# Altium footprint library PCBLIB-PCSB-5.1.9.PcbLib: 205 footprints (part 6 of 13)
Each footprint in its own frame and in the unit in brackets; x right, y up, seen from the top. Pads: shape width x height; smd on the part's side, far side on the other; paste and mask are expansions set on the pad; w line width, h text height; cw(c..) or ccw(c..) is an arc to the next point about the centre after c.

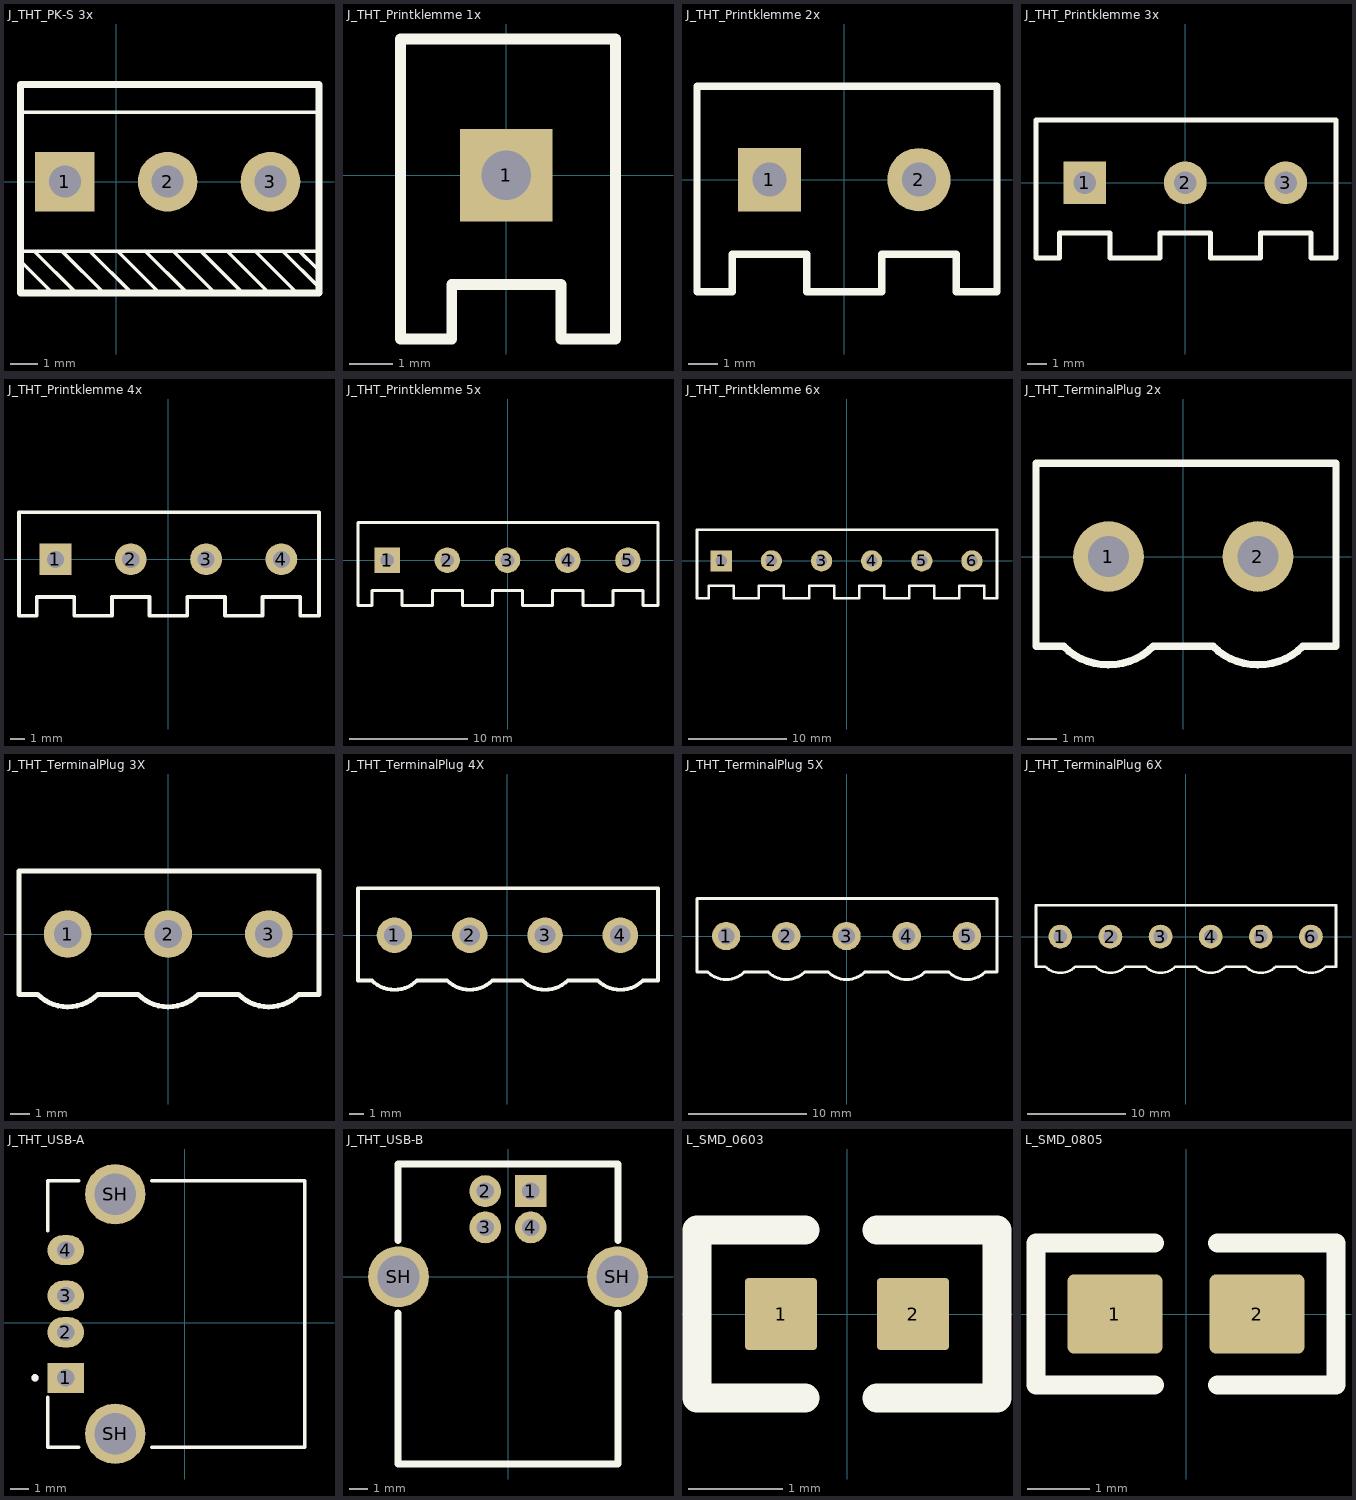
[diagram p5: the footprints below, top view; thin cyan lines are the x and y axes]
## J_THT_PK-S 3x [mm] "LB-2024-05-03g"
pads (3):
  rect 2.15x2.15 hole 1.15: 1(-1.85,0)
  round 2.15 hole 1.15: 2(1.85,0) 3(5.55,0)
Top Overlay:
  lines w0.127: -3.5,-2.5 6.5,-2.5 7.3,-2.5 ; -3.45,2.5 7.3,2.5 ; -3.4,-2.9 -2.3,-4 ; -1.95,-2.5 -0.45,-4 ; -1.45,-4 -2.95,-2.5 ; -0.95,-2.5 0.55,-4 ; 0.05,-2.5 1.55,-4 ; 1.05,-2.5 2.55,-4 ; 3.55,-4 2.05,-2.5 ; 4,-2.5 5.425,-3.925 ; 4.575,-4.025 3.05,-2.5 ; 5,-2.5 6.5,-4 ; 6,-2.5 7.3,-3.8 ; 7,-2.5 6.6,-2.5 7.25,-3.15 ; -2.95,-2.5 -2.95,-2.5 ; 2.05,-2.5 2.05,-2.5 ; 3.05,-2.5 3.05,-2.5 ; 3.05,-2.5 3.05,-2.5
  lines w0.254: -3.45,-4 -3.45,2.365 -3.45,3.5 7.3,3.5 7.3,-4 3.55,-4 -2.91,-4 -3.45,-4

## J_THT_Printklemme 1x [mm] "LB-2024-04-17"
pads (1):
  rect 2.15x2.15 hole 1.15: 1(0,0)
Top Overlay:
  lines w0.254: -2.46,-3.81 -2.46,2.365 -2.46,3.175 2.54,3.175 2.54,-3.81 1.27,-3.81 1.27,-2.54 -1.27,-2.54 -1.27,-3.81 -2.46,-3.81

## J_THT_Printklemme 2x [mm] "LB-2024-04-17"
pads (2):
  rect 2.15x2.15 hole 1.15: 1(-2.54,0)
  round 2.15 hole 1.15: 2(2.54,0)
Top Overlay:
  lines w0.254: 1.27,-3.81 1.27,-2.54 ; 1.27,-3.81 -1.27,-3.81 -1.27,-2.54 -3.81,-2.54 -3.81,-3.81 -5,-3.81 -5,2.365 -5,3.175 5.19,3.175 5.19,-3.81 3.81,-3.81 ; 1.27,-3.81 1.27,-2.54 ; 1.27,-2.54 3.81,-2.54 ; 3.81,-3.81 3.81,-2.54 ; 3.81,-3.81 3.81,-2.54

## J_THT_Printklemme 3x [mm] "LB-2024-04-17"
pads (3):
  rect 2.15x2.15 hole 1.15: 1(-5.08,0)
  round 2.15 hole 1.15: 2(0,0) 3(5.08,0)
Top Overlay:
  lines w0.254: -1.27,-3.81 -1.27,-2.54 ; -1.27,-3.81 -3.81,-3.81 -3.81,-2.54 -6.35,-2.54 -6.35,-3.81 -7.54,-3.81 -7.54,2.365 -7.54,3.175 2.65,3.175 7.62,3.175 7.62,-3.81 6.35,-3.81 6.35,-2.54 3.81,-2.54 3.81,-3.81 1.27,-3.81 ; -1.27,-3.81 -1.27,-2.54 ; -1.27,-2.54 1.27,-2.54 ; 1.27,-3.81 1.27,-2.54 ; 1.27,-3.81 1.27,-2.54

## J_THT_Printklemme 4x [mm] "LB-2024-04-17"
pads (4):
  rect 2.15x2.15 hole 1.15: 1(-7.62,0)
  round 2.15 hole 1.15: 2(-2.54,0) 3(2.54,0) 4(7.62,0)
Top Overlay:
  lines w0.254: -3.81,-3.81 -3.81,-2.54 ; -3.81,-3.81 -6.35,-3.81 -6.35,-2.54 -8.89,-2.54 -8.89,-3.81 -10.08,-3.81 -10.08,2.365 -10.08,3.175 0.11,3.175 10.16,3.175 10.16,-3.81 8.89,-3.81 8.89,-2.54 6.35,-2.54 6.35,-3.81 3.81,-3.81 3.81,-2.54 1.27,-2.54 1.27,-3.81 -1.27,-3.81 ; -3.81,-3.81 -3.81,-2.54 ; -3.81,-2.54 -1.27,-2.54 ; -1.27,-3.81 -1.27,-2.54 ; -1.27,-3.81 -1.27,-2.54

## J_THT_Printklemme 5x [mm] "LB-2024-04-17"
pads (5):
  rect 2.15x2.15 hole 1.15: 1(-10.16,0)
  round 2.15 hole 1.15: 2(-5.08,0) 3(0,0) 4(5.08,0) 5(10.16,0)
Top Overlay:
  lines w0.254: -6.35,-3.81 -6.35,-2.54 ; -6.35,-3.81 -8.89,-3.81 -8.89,-2.54 -11.43,-2.54 -11.43,-3.81 -12.62,-3.81 -12.62,2.365 -12.62,3.175 -2.43,3.175 12.7,3.175 12.7,-3.81 11.43,-3.81 11.43,-2.54 8.89,-2.54 8.89,-3.81 6.35,-3.81 6.35,-2.54 3.81,-2.54 3.81,-3.81 1.27,-3.81 1.27,-2.54 -1.27,-2.54 -1.27,-3.81 -3.81,-3.81 ; -6.35,-3.81 -6.35,-2.54 ; -6.35,-2.54 -3.81,-2.54 ; -3.81,-3.81 -3.81,-2.54 ; -3.81,-3.81 -3.81,-2.54

## J_THT_Printklemme 6x [mm] "LB-2024-04-17"
pads (6):
  rect 2.15x2.15 hole 1.15: 1(-12.7,0)
  round 2.15 hole 1.15: 2(-7.62,0) 3(-2.54,0) 4(2.54,0) 5(7.62,0) 6(12.7,0)
Top Overlay:
  lines w0.254: -8.89,-3.81 -8.89,-2.54 ; -8.89,-3.81 -11.43,-3.81 -11.43,-2.54 -13.97,-2.54 -13.97,-3.81 -15.16,-3.81 -15.16,2.365 -15.16,3.175 -4.97,3.175 15.24,3.175 15.24,-3.81 13.97,-3.81 13.97,-2.54 11.43,-2.54 11.43,-3.81 8.89,-3.81 8.89,-2.54 6.35,-2.54 6.35,-3.81 3.81,-3.81 3.81,-2.54 1.27,-2.54 1.27,-3.81 -1.27,-3.81 -1.27,-2.54 -3.81,-2.54 -3.81,-3.81 -6.35,-3.81 ; -8.89,-3.81 -8.89,-2.54 ; -8.89,-2.54 -6.35,-2.54 ; -6.35,-3.81 -6.35,-2.54 ; -6.35,-3.81 -6.35,-2.54

## J_THT_TerminalPlug 2x [mm] "LB-2024-04-17"
pads (2):
  round 2.4 hole 1.4: 1(-2.54,0) 2(2.54,0)
Top Overlay:
  lines w0.254: -5,-3.048 -4.064,-3.048 ccw(c-2.54,-1.524) -1.016,-3.048 1.016,-3.048 ccw(c2.54,-1.524) 4.064,-3.048 5.19,-3.048 5.19,3.175 -5,3.175 -5,2.365 -5,-3.048

## J_THT_TerminalPlug 3X [mm] "LB-2024-04-17"
pads (3):
  round 2.4 hole 1.4: 1(-5.08,0) 2(0,0) 3(5.08,0)
Top Overlay:
  lines w0.254: -7.54,-3.048 -7.54,2.365 -7.54,3.175 2.65,3.175 7.62,3.175 7.62,-3.048 6.604,-3.048 cw(c5.08,-1.524) 3.556,-3.048 1.524,-3.048 cw(c0,-1.524) -1.524,-3.048 -3.556,-3.048 cw(c-5.08,-1.524) -6.604,-3.048 -7.54,-3.048

## J_THT_TerminalPlug 4X [mm] "LB-2024-04-17"
pads (4):
  round 2.4 hole 1.4: 1(-7.62,0) 2(-2.54,0) 3(2.54,0) 4(7.62,0)
Top Overlay:
  lines w0.254: -10.08,-3.048 -10.08,2.365 -10.08,3.175 0.11,3.175 10.16,3.175 10.16,-3.048 9.144,-3.048 cw(c7.62,-1.524) 6.096,-3.048 4.064,-3.048 cw(c2.54,-1.524) 1.016,-3.048 -1.016,-3.048 cw(c-2.54,-1.524) -4.064,-3.048 -6.096,-3.048 cw(c-7.62,-1.524) -9.144,-3.048 -10.08,-3.048

## J_THT_TerminalPlug 5X [mm] "LB-2024-04-17"
pads (5):
  round 2.4 hole 1.4: 1(-10.16,0) 2(-5.08,0) 3(0,0) 4(5.08,0) 5(10.16,0)
Top Overlay:
  lines w0.254: -12.62,-3.048 -11.684,-3.048 ccw(c-10.16,-1.524) -8.636,-3.048 -6.604,-3.048 ccw(c-5.08,-1.524) -3.556,-3.048 -1.524,-3.048 ccw(c0,-1.524) 1.524,-3.048 3.556,-3.048 ccw(c5.08,-1.524) 6.604,-3.048 8.636,-3.048 ccw(c10.16,-1.524) 11.684,-3.048 12.7,-3.048 12.7,3.175 -2.43,3.175 -12.62,3.175 -12.62,2.365 -12.62,-3.048

## J_THT_TerminalPlug 6X [mm] "LB-2024-04-17"
pads (6):
  round 2.4 hole 1.4: 1(-12.7,0) 2(-7.62,0) 3(-2.54,0) 4(2.54,0) 5(7.62,0) 6(12.7,0)
Top Overlay:
  lines w0.254: -15.16,-3.048 -15.16,2.365 -15.16,3.175 -4.97,3.175 15.24,3.175 15.24,-3.048 14.224,-3.048 cw(c12.7,-1.524) 11.176,-3.048 9.144,-3.048 cw(c7.62,-1.524) 6.096,-3.048 4.064,-3.048 cw(c2.54,-1.524) 1.016,-3.048 -1.016,-3.048 cw(c-2.54,-1.524) -4.064,-3.048 -6.096,-3.048 cw(c-7.62,-1.524) -9.144,-3.048 -11.176,-3.048 cw(c-12.7,-1.524) -14.224,-3.048 -15.16,-3.048

## J_THT_USB-A [mm] "LB-2024-04-29"
pads (6):
  rect 2x1.65 hole 0.95: 1(-6.536,-3.032)
  oval 2x1.65 hole 0.95: 2(-6.536,-0.532) 3(-6.536,1.468) 4(-6.536,3.968)
  round 3.316 hole 2.3: SH(-3.826,-6.102) SH(-3.826,7.038)
Top Overlay:
  circle w0.2: c-8.226,-3.032 r0.1
  lines w0.2: -7.526,-4.097 -7.526,-6.832 -5.836,-6.832 ; -7.526,5.033 -7.526,7.768 -5.836,7.768 ; -1.816,-6.832 6.574,-6.832 6.574,7.768 -1.816,7.768
Mechanical 13:
  circle w0.2: c-8.226,-3.032 r0.1

## J_THT_USB-B [mm] "LB-2024-04-15"
pads (6):
  rect 1.75x1.75 hole 0.95: 1(1.25,4.71)
  round 1.75 hole 0.95: 2(-1.25,4.71) 3(-1.25,2.71) 4(1.25,2.71)
  round 3.346 hole 2.33: SH(-6.02,0) SH(6.02,0)
Top Overlay:
  lines w0.4: -6.05,-2 -6.05,-10.3 6.05,-10.3 6.05,-2 ; -6.05,2 -6.05,6.2 6.05,6.2 6.05,2

## L_SMD_0603 [mil] "LB-2024-04-17"
pads (2):
  rrect10% 30x30 smd paste-0.79 mask+1.97: 1(-27.5,0) 2(27.5,0)
Top Overlay:
  lines w12: -17.5,-35 -62.5,-35 -62.5,35 -17.5,35 ; 12.5,-35 62.5,-35 62.5,35 12.5,35

## L_SMD_0805 [mil] "LB-2024-04-17"
pads (2):
  rrect15% 60x50 smd paste-0.79 mask+1.97: 1(-45,0) 2(45,0)
Top Overlay:
  lines w12: -20,-45 -95,-45 -95,45 -20,45 ; 20,-45 95,-45 95,45 20,45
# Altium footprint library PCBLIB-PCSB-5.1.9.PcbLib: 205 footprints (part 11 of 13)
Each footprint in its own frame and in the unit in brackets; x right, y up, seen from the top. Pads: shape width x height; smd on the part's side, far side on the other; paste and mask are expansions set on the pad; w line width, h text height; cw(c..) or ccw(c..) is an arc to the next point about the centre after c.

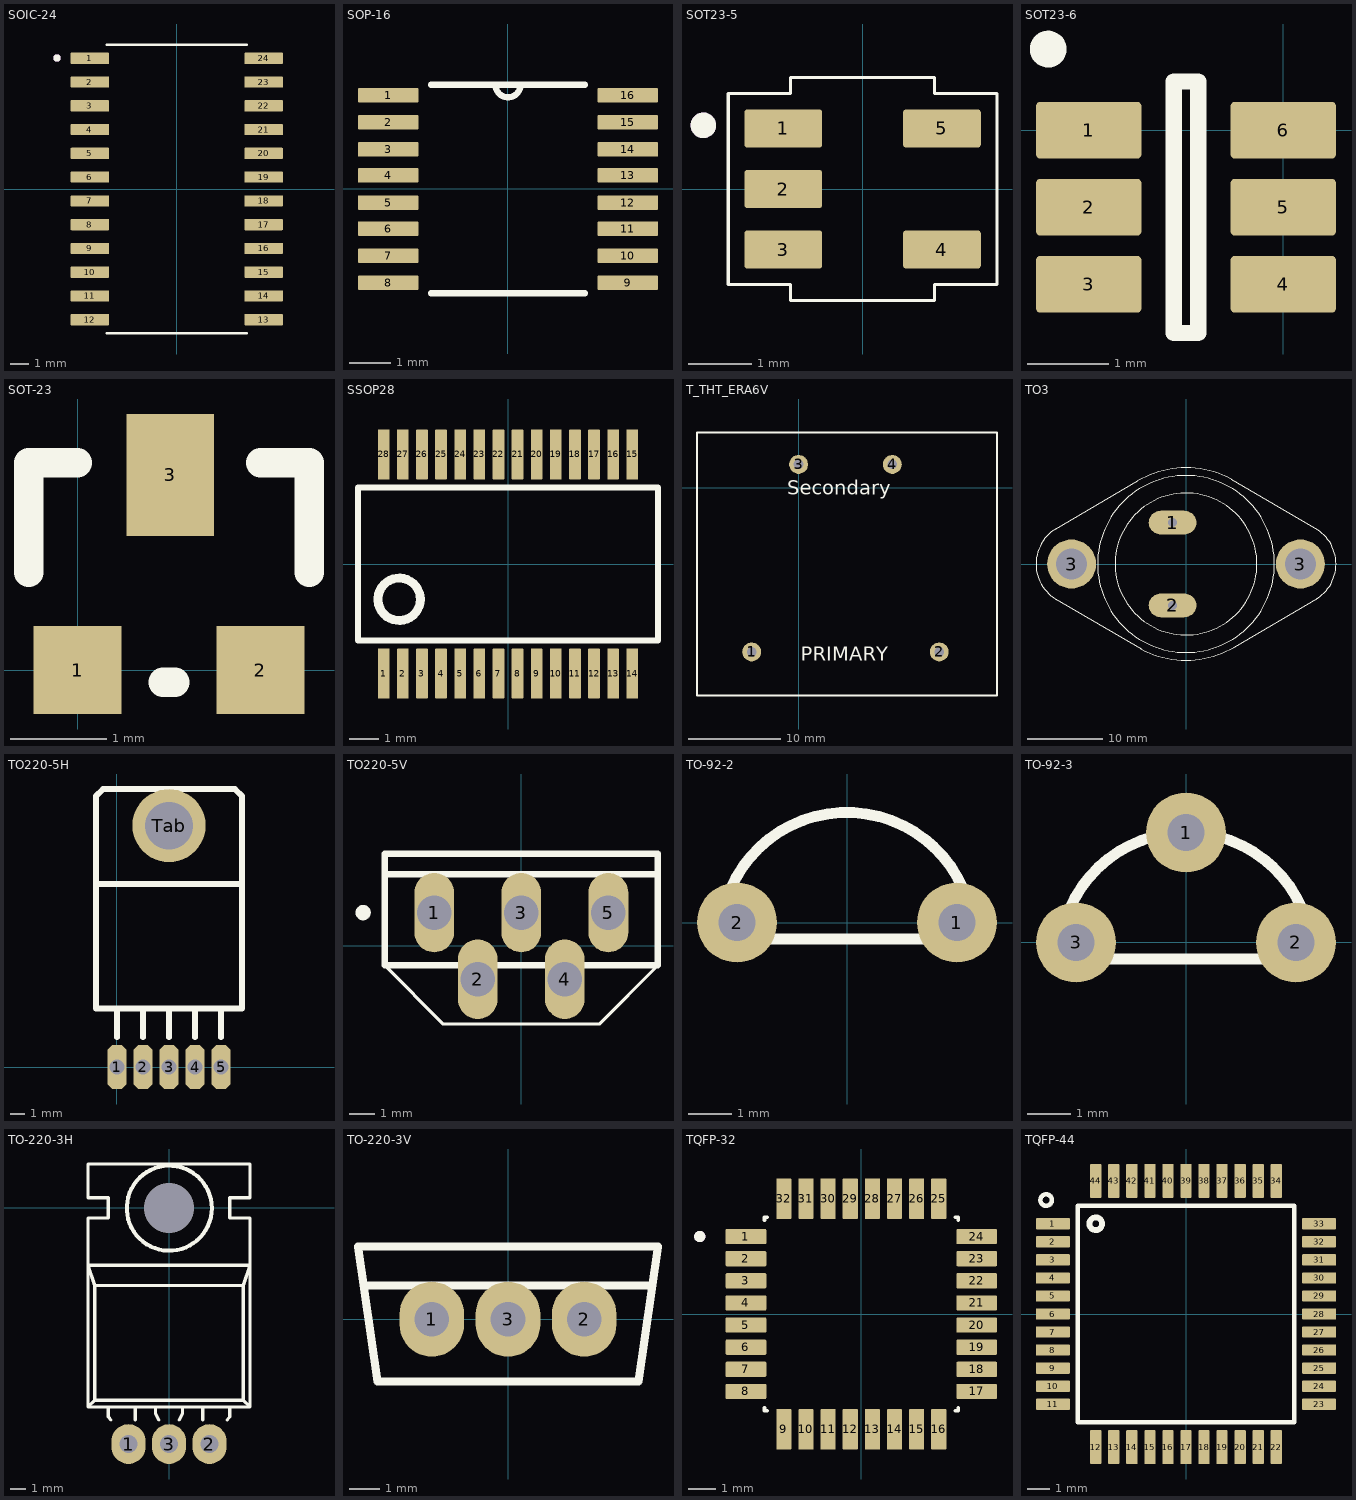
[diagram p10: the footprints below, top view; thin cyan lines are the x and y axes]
## SOIC-24 [mm]
height 2.65
pads (24):
  rrect15% 2.06x0.6 smd paste-0.02 mask+0.05: 1(-4.64,6.985) 2(-4.64,5.715) 3(-4.64,4.445) 4(-4.64,3.175) 5(-4.64,1.905) 6(-4.64,0.635) 7(-4.64,-0.635) 8(-4.64,-1.905) 9(-4.64,-3.175) 10(-4.64,-4.445) 11(-4.64,-5.715) 12(-4.64,-6.985) 13(4.64,-6.985) 14(4.64,-5.715) 15(4.64,-4.445) 16(4.64,-3.175) 17(4.64,-1.905) 18(4.64,-0.635) 19(4.64,0.635) 20(4.64,1.905) 21(4.64,3.175) 22(4.64,4.445) 23(4.64,5.715) 24(4.64,6.985)
Top Overlay:
  circle w0.2: c-6.4,7 r0.1
  lines w0.127: -3.75,-7.7 3.75,-7.7 ; -3.75,7.7 3.75,7.7
Mechanical 13:
  circle w0.2: c-6.4,7 r0.1

## SOP-16 [mil] "LB-2024-04-17"
pads (16):
  rrect15% 58x14 smd paste-0.79 mask+1.97: 1(-115,90) 2(-115,64) 3(-115,38) 4(-115,13) 5(-115,-13) 6(-115,-38) 7(-115,-64) 8(-115,-90) 9(115,-90) 10(115,-64) 11(115,-38) 12(115,-13) 13(115,13) 14(115,38) 15(115,64) 16(115,90)
Top Overlay:
  lines w6: -74,-100 74,-100 ; -74,100 -12,100 ; 74,100 12,100 ; -12,100 ccw(c0,100) 12,100 ; -12,100 12,100
Mechanical 13:
  lines w0: -12,100 ccw(c0,100) 12,100

## SOT23-5 [mm]
pads (5):
  rrect15% 1.22x0.6 smd paste-0.02 mask+0.05: 1(-1.245,0.95) 2(-1.245,0) 3(-1.245,-0.95) 4(1.245,-0.95) 5(1.245,0.95)
Top Overlay:
  circle w0.2: c-2.5,1 r0.1
  lines w0.05: -2.11,-1.5 -2.11,1.5 -1.13,1.5 -1.13,1.75 1.13,1.75 1.13,1.5 2.11,1.5 2.11,-1.5 1.13,-1.5 1.13,-1.75 -1.13,-1.75 -1.13,-1.5 -2.11,-1.5
Mechanical 13:
  circle w0.2: c-2.5,1 r0.1

## SOT23-6 [mm] "LB-2024-04-25"
height 1.45
pads (6):
  rrect15% 1.3x0.7 smd paste-0.02 mask+0.05: 1(-2.4,0) 2(-2.4,-0.95) 3(-2.4,-1.9) 4(0,-1.9) 5(0,-0.95) 6(0,0)
Top Overlay:
  circle w0.254: c-2.9,1 r0.1
  lines w0.2: -1.35,-2.5 -1.05,-2.5 -1.05,0.6 -1.35,0.6 -1.35,-2.5

## SOT-23 [mil]
pads (3):
  rect 36x36 smd: 1(0,0) 2(75,0)
  rect 36x50 smd: 3(38,80)
Top Overlay:
  lines w12: -20,40 -20,85 0,85 ; 35,-5 40,-5 ; 75,85 95,85 95,40

## SSOP28 [mm] "LB-2024-09-01"
pads (28):
  rrect15% 0.4x1.7 smd paste-0.02 mask+0.05: 1(-4.225,-3.725) 2(-3.575,-3.725) 3(-2.925,-3.725) 4(-2.275,-3.725) 5(-1.625,-3.725) 6(-0.975,-3.725) 7(-0.325,-3.725) 8(0.325,-3.725) 9(0.975,-3.725) 10(1.625,-3.725) 11(2.275,-3.725) 12(2.925,-3.725) 13(3.575,-3.725) 14(4.225,-3.725) 15(4.225,3.725) 16(3.575,3.725) 17(2.925,3.725) 18(2.275,3.725) 19(1.625,3.725) 20(0.975,3.725) 21(0.325,3.725) 22(-0.325,3.725) 23(-0.975,3.725) 24(-1.625,3.725) 25(-2.275,3.725) 26(-2.925,3.725) 27(-3.575,3.725) 28(-4.225,3.725)
Top Overlay:
  circle w0.3: c-3.7,-1.2 r0.721
  lines w0.203: -5.1,-2.6 -5.1,2.6 5.1,2.6 5.1,-2.6 -5.1,-2.6

## T_THT_ERA6V [mm] "LB-2024-04-17"
pads (4):
  round 2.05 hole 1.05: 1(-5.08,-17.78) 2(15.24,-17.78) 3(0,2.54) 4(10.16,2.54)
Top Overlay:
  lines w0.254: -11,-22.5 21.5,-22.5 21.5,6 -11,6 -11,-22.5
  text "PRIMARY" at 0.254,-18.746 h1.52
  text "Secondary" at -1.246,-0.738 h1.52

## TO3 [mil] "LB-2024-04-17"
pads (4):
  oval 248x124 hole 47.05: 1(-70,215) 2(-70,-215)
  round 255 hole 162: 3(-595,0) 3(595,0)
Top Overlay:
  circle w6: c0,0 r369
  circle w2: c0,0 r460
  lines w6: -680,180 -250,433 cw(c0,0) 0,500 cw(c0,0) 234.74,441.47 ; -679,-181 -234,-442 ; -676.7,-182.58 cw(c-567,0) -780,0 cw(c-567,0) -673.5,184.46 ; -234.74,-441.47 ccw(c0,0) 0,-500 ccw(c0,0) 250,-433.01 ; 235,441 684,178 ; 251,-433 684,-178 ; 683.01,-178.64 ccw(c567,0) 780,0 ccw(c567,0) 683.01,178.64
Mechanical 13:
  circle w6: c595,0 r85
  circle w6: c-595,0 r85

## TO220-5H [mm] "LB-2024-04-19"
height 5
pads (6):
  oct 1.3x3 hole 1.05: 1(0,0) 2(1.778,0) 3(3.556,0) 4(5.334,0) 5(7.112,0)
  round 5 hole 3.25: Tab(3.556,16.5)
Top Overlay:
  lines w0.4: 0,2.032 0,4 ; 1.778,2.032 1.778,4 ; 3.556,2.032 3.556,4 ; 3.556,16.5 3.556,19 ; 5.334,2.032 5.334,4 ; 7.112,2.032 7.112,4 ; -1.444,12.5 8.556,12.5 ; -1.444,12.5 -1.444,4 8.556,4 8.556,12.5 ; -1.444,12.5 -1.444,18.5 -0.944,19 8.056,19 8.556,18.5 ; 8.556,12.5 8.556,18.5 ; 8.556,18.5 8.556,18.5

## TO220-5V [mm] "LB-2024-0419"
height 16.51
pads (5):
  oval 1.55x3.1 hole 1.35: 1(-3.4,1.3) 2(-1.7,-1.3) 3(0,1.3) 4(1.7,-1.3) 5(3.4,1.3)
Top Overlay:
  circle w0.2: c-6.175,1.3 r0.2
  rectangle: -6.325,1.15 -5.975,1.5
  lines w0.127: -5.335,-0.761 -3.048,-3.048 3.048,-3.048 5.335,-0.761 5.335,3.59 -5.335,3.59 -5.335,-0.761
  lines w0.254: -5.334,2.794 5.334,2.794 ; 5.334,2.794 5.334,-0.762 -5.334,-0.762 -5.334,3.589 -5.335,3.59 5.333,3.59 5.334,3.589 5.334,2.794

## TO-92-2 [mm] "LB-2024-04-18"
pads (2):
  round 1.85 hole 0.85: 1(2.54,0) 2(-2.54,0)
Top Overlay:
  lines w0.254: -2.927,-0.381 cw(c-0.003,-0.381) 2.921,-0.381 -2.927,-0.381

## TO-92-3 [mm] "LB-2024-04-17"
pads (3):
  round 1.85 hole 0.85: 1(0,2.54) 2(2.54,0) 3(-2.54,0)
Top Overlay:
  lines w0.254: -2.927,-0.381 cw(c-0.003,-0.381) 2.921,-0.381 -2.927,-0.381

## TO-220-3H [mm] "LB-2024-04-17"
pads (4):
  round 0 hole 3.15: 0(0,0)
  oval 2.15x2.5 hole 1.15: 1(-2.54,-14.817) 2(2.54,-14.817) 3(0,-14.817)
Top Overlay:
  circle w0.254: c0.017,-0.02 r2.667
  lines w0.2: -3.81,-13.123 -3.81,-12.488 ; -3.762,-13.155 -3.647,-13.317 ; -2.117,-13.317 -2.117,-12.488 ; -0.847,-12.488 -0.847,-12.912 -0.635,-13.317 ; 0.635,-13.317 0.847,-12.912 0.847,-12.488 ; 2.117,-13.317 2.117,-12.488 ; 3.655,-13.317 3.818,-13.099 ; 3.81,-13.123 3.81,-12.488 ; -5.08,-12.488 -5.08,-0.635 -3.81,-0.635 -3.81,0.635 -5.08,0.635 -5.08,2.752 5.08,2.752 5.08,0.635 3.81,0.635 3.81,-0.635 5.08,-0.635 5.08,-12.488 ; -5.08,-12.488 5.08,-12.488 ; -5.08,-12.488 -4.657,-12.065 ; -4.657,-12.065 -4.657,-4.868 ; -4.657,-12.065 4.657,-12.065 ; -4.657,-4.868 -5.08,-3.598 5.08,-3.598 4.657,-4.868 ; -4.657,-4.868 4.657,-4.868 ; 4.657,-12.065 4.657,-4.868 ; 4.657,-12.065 5.08,-12.488

## TO-220-3V [mm] "LB-2024-04-17"
pads (3):
  oval 2.15x2.5 hole 1.15: 1(-2.54,0) 2(2.54,0) 3(0,0)
Top Overlay:
  lines w0.254: -4.812,1.125 4.808,1.125 ; -5,2.425 -4.35,-2.075 0,-2.075 4.35,-2.075 5,2.425 0,2.425 -5,2.425

## TQFP-32 [mm] "LB-2024-04-19"
height 1.2
pads (32):
  rrect15% 1.47x0.55 smd paste-0.02 mask+0.05: 1(-4.17,2.8) 2(-4.17,2) 3(-4.17,1.2) 4(-4.17,0.4) 5(-4.17,-0.4) 6(-4.17,-1.2) 7(-4.17,-2) 8(-4.17,-2.8) 17(4.17,-2.8) 18(4.17,-2) 19(4.17,-1.2) 20(4.17,-0.4) 21(4.17,0.4) 22(4.17,1.2) 23(4.17,2) 24(4.17,2.8)
  rrect15% 0.55x1.47 smd paste-0.02 mask+0.05: 9(-2.8,-4.17) 10(-2,-4.17) 11(-1.2,-4.17) 12(-0.4,-4.17) 13(0.4,-4.17) 14(1.2,-4.17) 15(2,-4.17) 16(2.8,-4.17) 25(2.8,4.17) 26(2,4.17) 27(1.2,4.17) 28(0.4,4.17) 29(-0.4,4.17) 30(-1.2,4.17) 31(-2,4.17) 32(-2.8,4.17)
Top Overlay:
  circle w0.2: c-5.84,2.8 r0.1
  lines w0.127: -3.5,-3.395 -3.5,-3.5 -3.395,-3.5 ; -3.5,3.395 -3.5,3.5 -3.395,3.5 ; 3.395,-3.5 3.5,-3.5 3.5,-3.395 ; 3.395,3.5 3.5,3.5 3.5,3.395
Mechanical 13:
  circle w0.2: c-5.84,2.8 r0.1

## TQFP-44 [mm] "LB-2024-06-15"
pads (44):
  rrect15% 1.5x0.5 smd paste-0.02 mask+0.05: 1(-5.9,4) 2(-5.9,3.2) 3(-5.9,2.4) 4(-5.9,1.6) 5(-5.9,0.8) 6(-5.9,0) 7(-5.9,-0.8) 8(-5.9,-1.6) 9(-5.9,-2.4) 10(-5.9,-3.2) 11(-5.9,-4) 23(5.9,-4) 24(5.9,-3.2) 25(5.9,-2.4) 26(5.9,-1.6) 27(5.9,-0.8) 28(5.9,0) 29(5.9,0.8) 30(5.9,1.6) 31(5.9,2.4) 32(5.9,3.2) 33(5.9,4)
  rrect15% 0.5x1.5 smd paste-0.02 mask+0.05: 12(-4,-5.9) 13(-3.2,-5.9) 14(-2.4,-5.9) 15(-1.6,-5.9) 16(-0.8,-5.9) 17(0,-5.9) 18(0.8,-5.9) 19(1.6,-5.9) 20(2.4,-5.9) 21(3.2,-5.9) 22(4,-5.9) 34(4,5.9) 35(3.2,5.9) 36(2.4,5.9) 37(1.6,5.9) 38(0.8,5.9) 39(0,5.9) 40(-0.8,5.9) 41(-1.6,5.9) 42(-2.4,5.9) 43(-3.2,5.9) 44(-4,5.9)
Top Overlay:
  circle w0.254: c-4,4 r0.283
  circle w0.2: c-6.2,5.05 r0.254
  lines w0.203: -4.8,-4.8 4.8,-4.8 4.8,4.8 -4.8,4.8 -4.8,-4.8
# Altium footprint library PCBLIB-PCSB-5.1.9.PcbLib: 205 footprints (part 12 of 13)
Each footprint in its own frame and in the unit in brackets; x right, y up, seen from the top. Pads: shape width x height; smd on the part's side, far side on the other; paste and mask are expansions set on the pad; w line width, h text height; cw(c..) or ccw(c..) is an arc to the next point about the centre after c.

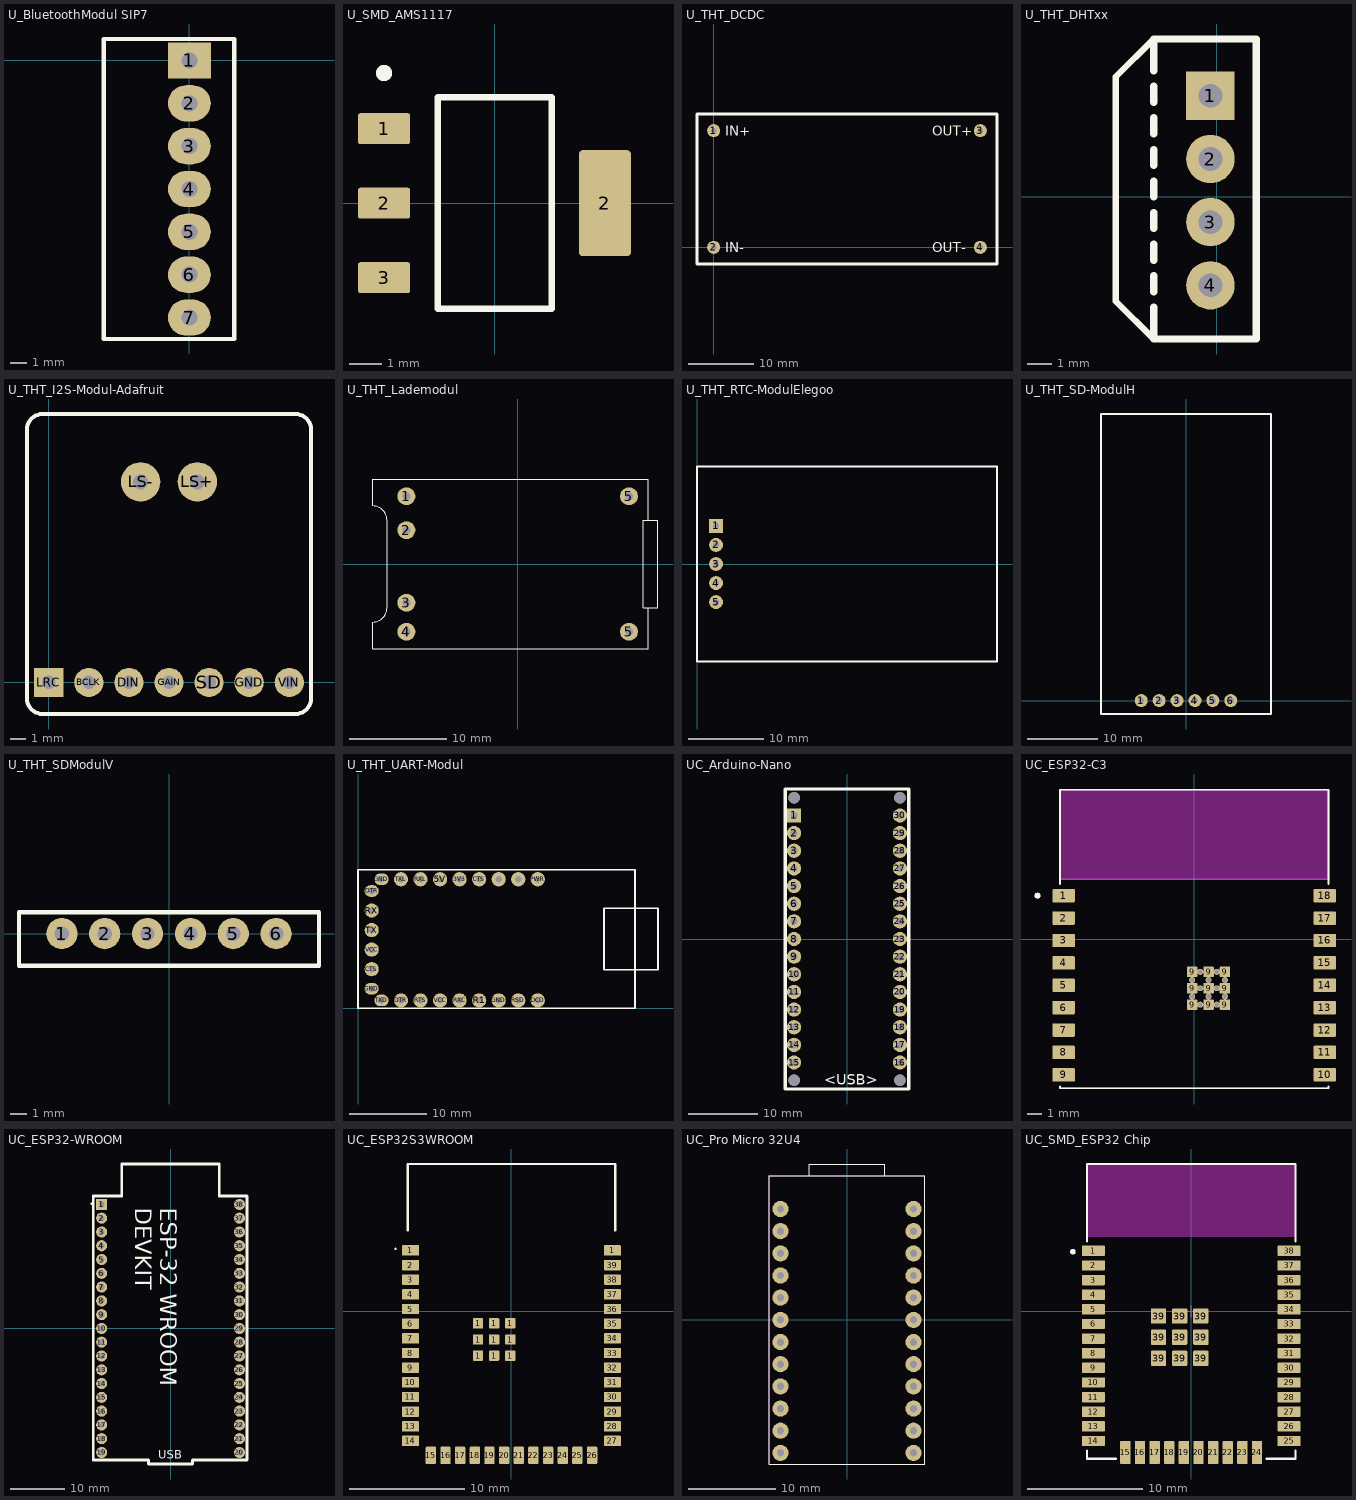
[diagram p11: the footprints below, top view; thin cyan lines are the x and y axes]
## U_BluetoothModul SIP7 [mm] "LB-2024-04-19"
pads (7):
  rect 2.54x2.15 hole 0.95: 1(0,0)
  oval 2.54x2.15 hole 0.95: 2(0,-2.54) 3(0,-5.08) 4(0,-7.62) 5(0,-10.16) 6(0,-12.7) 7(0,-15.24)
Top Overlay:
  lines w0.254: -5.08,-16.51 2.667,-16.51 2.667,1.27 -5.08,1.27 -5.08,-16.51

## U_SMD_AMS1117 [mm] "LB-2024-04-17"
pads (4):
  rrect15% 1.604x0.952 smd paste-0.02 mask+0.05: 1(-3.395,2.29) 2(-3.395,0) 3(-3.395,-2.29)
  rrect15% 1.604x3.262 smd paste-0.02 mask+0.05: 2(3.395,0)
Top Overlay:
  circle w0.25: c-3.395,4 r0.125
  lines w0.2: -1.753,-3.253 1.753,-3.253 1.753,3.253 -1.753,3.253 -1.753,-3.253
Mechanical 5:

## U_THT_DCDC [mm] "LB-2024-04-17"
pads (4):
  round 2 hole 0.85: 1(0,17.78) 2(0,0) 3(40.64,17.78) 4(40.64,0)
Top Overlay:
  lines w0.4: -2.54,-2.54 -2.54,20.32 43.18,20.32 43.18,-2.54 -2.54,-2.54
  text "IN+" at 1.778,17.018 h1.52
  text "IN-" at 1.778,-0.762 h1.52
  text "OUT+" at 33.274,17.018 h1.52
  text "OUT-" at 33.274,-0.762 h1.52

## U_THT_DHTxx [mm] "LB-2024-04-19"
pads (4):
  rect 1.95x1.95 hole 0.95: 1(-0.254,4.064)
  round 1.95 hole 0.95: 2(-0.254,1.524) 3(-0.254,-1.016) 4(-0.254,-3.556)
Top Overlay:
  lines w0.254: -2.54,-5.715 -4.064,-4.191 -4.064,4.826 -2.54,6.35
  lines w0.3: -2.54,-4.445 -2.54,-5.715 1.59,-5.715 1.59,6.35 -2.54,6.35 -2.54,5.08 ; -2.54,-3.81 -2.54,-3.175 ; -2.54,-2.54 -2.54,-1.905 ; -2.54,-1.27 -2.54,-0.635 ; -2.54,0 -2.54,0.635 ; -2.54,1.27 -2.54,1.905 ; -2.54,2.54 -2.54,3.175 ; -2.54,3.81 -2.54,4.445

## U_THT_I2S-Modul-Adafruit [mm] "LB-2024-05-02"
pads (9):
  round 1.85 hole 0.85: BCLK(2.54,0) DIN(5.08,0) GAIN(7.62,0) GND(12.7,0) SD(10.16,0) VIN(15.24,0)
  rect 1.85x1.85 hole 0.85: LRC(0,0)
  round 2.5 hole 0.95: LS+(9.42,12.7) LS-(5.82,12.7)
Top Overlay:
  lines w0.254: -1.38,-1 ccw(c-0.38,-1) -0.38,-2 7.62,-2 15.62,-2 ccw(c15.62,-1) 16.62,-1 16.62,16 ccw(c15.62,16) 15.62,17 -0.38,17 ccw(c-0.38,16) -1.38,16 -1.38,-1

## U_THT_Lademodul [mm] "LB-2024-04-25"
pads (6):
  round 1.85 hole 0.85: 1(-11.5,7) 2(-11.5,3.5) 3(-11.5,-4) 4(-11.5,-7) 5(11.5,-7) 5(11.5,7)
Top Overlay:
  lines w0.127: 13.5,-4.5 13.5,-8.75 -15,-8.75 -15,-6 ccw(c-15,-4.5) -13.5,-4.5 -13.5,4.5 ccw(c-15,4.5) -15,6 ; 13.5,4.5 13.5,8.75 -15,8.75 -15,6 ; -15,6 -15,6 ; 13,-4.5 13,0 13,4.5 14.5,4.5 14.5,-4.5 13,-4.5

## U_THT_RTC-ModulElegoo [mm] "LB-2024-04-19"
pads (5):
  rect 1.85x1.85 hole 0.85: 1(2.54,5.08)
  round 1.85 hole 0.85: 2(2.54,2.54) 3(2.54,0) 4(2.54,-2.54) 5(2.54,-5.08)
Top Overlay:
  lines w0.254: 40,0 40,13 ; 40,13 40,-13 0,-13 0,13 40,13

## U_THT_SD-ModulH [mm] "LB-2024-04-19"
pads (6):
  round 1.85 hole 0.85: 1(-6.35,0) 2(-3.81,0) 3(-1.27,0) 4(1.27,0) 5(3.81,0) 6(6.35,0)
Top Overlay:
  lines w0.254: -12.065,-1.905 12.065,-1.905 12.065,40.64 -12.065,40.64 -12.065,-1.905

## U_THT_SDModulV [mm] "LB-2024-04-19"
pads (6):
  round 1.85 hole 0.85: 1(-6.35,0) 2(-3.81,0) 3(-1.27,0) 4(1.27,0) 5(3.81,0) 6(6.35,0)
Top Overlay:
  lines w0.254: -8.89,-1.905 -8.89,1.27 8.89,1.27 8.89,-1.905 -8.89,-1.905

## U_THT_UART-Modul [mm] "LB-2024-04-15"
pads (24):
  round 1.85 hole 0.85: 3V3(13.208,16.764) 5V(10.668,16.764) CTS(1.778,5.08) CTS(15.748,16.764) DCD(23.368,1.016) DTR(5.588,1.016) ENTEN(20.828,16.764) GND(18.288,1.016) PWR(23.368,16.764) R1(15.748,1.016) RSD(20.828,1.016) RTS(8.128,1.016) RX(1.778,12.7) RXC(13.208,1.016) RXL(8.128,16.764) SLEEP(18.288,16.764) TX(1.778,10.16) TXL(5.588,16.764) VCC(1.778,7.62) VCC(10.668,1.016)
  oval 1.85x1.5 hole 0.85: DTR(1.778,15.24) GND(1.778,2.54) GND(3.048,16.764) TXD(3.048,1.016)
Top Overlay:
  lines w0.254: 0,0 0,18 36,18 36,0 0,0 ; 32,5 39,5 39,13 34,13 32,13 32,5

## UC_Arduino-Nano [mm] "LB-2024-04-18"
pads (34):
  rect 2.05x2.05 hole 1.05: 1(-7.62,17.78)
  round 2.05 hole 1.05: 2(-7.62,15.24) 3(-7.62,12.7) 4(-7.62,10.16) 5(-7.62,7.62) 6(-7.62,5.08) 7(-7.62,2.54) 8(-7.62,0) 9(-7.62,-2.54) 10(-7.62,-5.08) 11(-7.62,-7.62) 12(-7.62,-10.16) 13(-7.62,-12.7) 14(-7.62,-15.24) 15(-7.62,-17.78) 16(7.62,-17.78) 17(7.62,-15.24) 18(7.62,-12.7) 19(7.62,-10.16) 20(7.62,-7.62) 21(7.62,-5.08) 22(7.62,-2.54) 23(7.62,0) 24(7.62,2.54) 25(7.62,5.08) 26(7.62,7.62) 27(7.62,10.16) 28(7.62,12.7) 29(7.62,15.24) 30(7.62,17.78)
  round 1.651 hole 1.651 unplated: ""(-7.62,-20.32) ""(-7.62,20.32) ""(7.62,-20.32) ""(7.62,20.32)
Top Overlay:
  lines w0.5: -8.89,-21.59 8.89,-21.59 8.89,21.59 -8.89,21.59 -8.89,-21.59
  text "<USB>" at -3.302,-20.955 h1.52

## UC_ESP32-C3 [mm] "LB-2024-09-01"
pads (39):
  rrect15% 1.5x0.9 smd paste-0.02 mask+0.05: 1(-8.75,2.9) 2(-8.75,1.4) 3(-8.75,-0.1) 4(-8.75,-1.6) 5(-8.75,-3.1) 6(-8.75,-4.6) 7(-8.75,-6.1) 8(-8.75,-7.6) 9(-8.75,-9.1) 10(8.75,-9.1) 11(8.75,-7.6) 12(8.75,-6.1) 13(8.75,-4.6) 14(8.75,-3.1) 15(8.75,-1.6) 16(8.75,-0.1) 17(8.75,1.4) 18(8.75,2.9)
  rrect15% 0.7x0.7 smd paste-0.02 mask+0.05: 9(-0.14,-4.4) 9(-0.14,-3.3) 9(-0.14,-2.2) 9(0.96,-4.4) 9(0.96,-3.3) 9(0.96,-2.2) 9(2.06,-4.4) 9(2.06,-3.3) 9(2.06,-2.2)
  round 0.4 hole 0.3 mask+0: 9(-0.14,-3.85) 9(-0.14,-2.75) 9(0.41,-4.4) 9(0.41,-3.3) 9(0.41,-2.2) 9(0.96,-3.85) 9(0.96,-2.75) 9(1.51,-4.4) 9(1.51,-3.3) 9(1.51,-2.2) 9(2.06,-3.85) 9(2.06,-2.75)
Top Overlay:
  circle w0.2: c-10.5,2.9 r0.1
  lines w0.127: -9,-9.87 -9,-10 9,-10 9,-9.87 ; -9,3.67 -9,10 9,10 9,3.67
Keep-Out Layer:
  region: 9,4 -9,4 -9,10 9,10
  region: 9,4 -9,4 -9,10 9,10
Mechanical 13:
  circle w0.2: c-10.5,2.9 r0.1
  lines w0.127: -9,-10 9,-10 ; -9,4 9,4 9,10 -9,10 -9,4

## UC_ESP32-WROOM [mm] "LB-2024-04-18"
pads (38):
  rect 2.05x2.05 hole 1.05: 1(-12.7,22.85)
  round 2.05 hole 1.05: 2(-12.7,20.31) 3(-12.7,17.77) 4(-12.7,15.23) 5(-12.7,12.69) 6(-12.7,10.15) 7(-12.7,7.61) 8(-12.7,5.07) 9(-12.7,2.53) 10(-12.7,-0.01) 11(-12.7,-2.55) 12(-12.7,-5.09) 13(-12.7,-7.63) 14(-12.7,-10.17) 15(-12.7,-12.71) 16(-12.7,-15.25) 17(-12.7,-17.79) 18(-12.7,-20.33) 19(-12.7,-22.87) 20(12.7,-22.87) 21(12.7,-20.33) 22(12.7,-17.79) 23(12.7,-15.25) 24(12.7,-12.71) 25(12.7,-10.17) 26(12.7,-7.63) 27(12.7,-5.09) 28(12.7,-2.55) 29(12.7,-0.01) 30(12.7,2.53) 31(12.7,5.07) 32(12.7,7.61) 33(12.7,10.15) 34(12.7,12.69) 35(12.7,15.23) 36(12.7,17.77) 37(12.7,20.31) 38(12.7,22.85)
Top Overlay:
  circle w0.2: c-14.57,22.97 r0.1
  lines w0.5: -14.224,-24.257 -14.224,24.384 -9,24.384 -9,30.3 9,30.3 9,24.384 14.097,24.384 14.097,-24.257 4.06,-24.257 4.06,-25 -4.07,-25 -4.07,-24.257 -14.224,-24.257
  text "ESP-32 WROOM / DEVKIT" at -6.477,22.225 h3.05
  text "USB" at -2.286,-24.003 h1.52
Mechanical 13:
  circle w0.2: c-14.57,22.97 r0.1

## UC_ESP32S3WROOM [mm] "LB-2025-01-10"
pads (49):
  rrect20% 1.5x0.9 smd paste-0.02 mask+0.05: 1(-8.75,5.26) 1(8.75,5.26) 2(-8.75,3.99) 3(-8.75,2.72) 4(-8.75,1.45) 5(-8.75,0.18) 6(-8.75,-1.09) 7(-8.75,-2.36) 8(-8.75,-3.63) 9(-8.75,-4.9) 10(-8.75,-6.17) 11(-8.75,-7.44) 12(-8.75,-8.71) 13(-8.75,-9.98) 14(-8.75,-11.25) 27(8.75,-11.25) 28(8.75,-9.98) 29(8.75,-8.71) 30(8.75,-7.44) 31(8.75,-6.17) 32(8.75,-4.9) 33(8.75,-3.63) 34(8.75,-2.36) 35(8.75,-1.09) 36(8.75,0.18) 37(8.75,1.45) 38(8.75,2.72) 39(8.75,3.99)
  rrect20% 0.9x0.9 smd paste-0.02 mask+0.05: 1(-2.9,-3.86) 1(-2.9,-2.46) 1(-2.9,-1.06) 1(-1.5,-3.86) 1(-1.5,-2.46) 1(-1.5,-1.06) 1(-0.1,-3.86) 1(-0.1,-2.46) 1(-0.1,-1.06)
  rrect20% 0.9x1.5 smd paste-0.02 mask+0.05: 15(-6.985,-12.5) 16(-5.715,-12.5) 17(-4.445,-12.5) 18(-3.175,-12.5) 19(-1.905,-12.5) 20(-0.635,-12.5) 21(0.635,-12.5) 22(1.905,-12.5) 23(3.175,-12.5) 24(4.445,-12.5) 25(5.715,-12.5) 26(6.985,-12.5)
Top Overlay:
  lines w0.1: -10.1,5.4 ccw(c-10.05,5.4) -10,5.4 ccw(c-10.05,5.4) -10.1,5.4
  lines w0.2: -9,7 -9,12.75 9,12.75 9,7

## UC_Pro Micro 32U4 [mm] "LB-2024-04-18"
pads (24):
  round 1.85 hole 0.85 mask+0.05: J3_1(-7.62,-15.24) J3_2(-7.62,-12.7) J3_3(-7.62,-10.16) J3_4(-7.62,-7.62) J3_5(-7.62,-5.08) J3_6(-7.62,-2.54) J3_7(-7.62,0) J3_8(-7.62,2.54) J3_9(-7.62,5.08) J3_10(-7.62,7.62) J3_11(-7.62,10.16) J3_12(-7.62,12.7) J4_1(7.62,12.7) J4_2(7.62,10.16) J4_3(7.62,7.62) J4_4(7.62,5.08) J4_5(7.62,2.54) J4_6(7.62,0) J4_7(7.62,-2.54) J4_8(7.62,-5.08) J4_9(7.62,-7.62) J4_10(7.62,-10.16) J4_11(7.62,-12.7) J4_12(7.62,-15.24)
Top Overlay:
  lines w0.127: -4.32,16.51 -4.32,17.855 4.32,17.855 4.32,16.51 ; -8.89,-16.51 -8.89,16.51 8.89,16.51 8.89,-16.51 -8.89,-16.51
Mechanical 13:
  lines w0.127: -8.89,-16.51 -8.89,16.51 -4.32,16.51 4.32,16.51 8.89,16.51 8.89,-16.51 -8.89,-16.51

## UC_SMD_ESP32 Chip [mm] "LB-2024-04-18"
pads (47):
  rrect15% 2x0.9 smd paste-0.02 mask+0.05: 1(-8.5,5.26) 2(-8.5,3.99) 3(-8.5,2.72) 4(-8.5,1.45) 5(-8.5,0.18) 6(-8.5,-1.09) 7(-8.5,-2.36) 8(-8.5,-3.63) 9(-8.5,-4.9) 10(-8.5,-6.17) 11(-8.5,-7.44) 12(-8.5,-8.71) 13(-8.5,-9.98) 14(-8.5,-11.25) 25(8.5,-11.25) 26(8.5,-9.98) 27(8.5,-8.71) 28(8.5,-7.44) 29(8.5,-6.17) 30(8.5,-4.9) 31(8.5,-3.63) 32(8.5,-2.36) 33(8.5,-1.09) 34(8.5,0.18) 35(8.5,1.45) 36(8.5,2.72) 37(8.5,3.99) 38(8.5,5.26)
  rrect15% 0.9x2 smd paste-0.02 mask+0.05: 15(-5.715,-12.25) 16(-4.445,-12.25) 17(-3.175,-12.25) 18(-1.905,-12.25) 19(-0.635,-12.25) 20(0.635,-12.25) 21(1.905,-12.25) 22(3.175,-12.25) 23(4.445,-12.25) 24(5.715,-12.25)
  rrect15% 1.33x1.33 smd paste-0.02 mask+0.05: 39(-2.835,-4.075) 39(-2.835,-2.24) 39(-2.835,-0.405) 39(-1,-4.075) 39(-1,-2.24) 39(-1,-0.405) 39(0.835,-4.075) 39(0.835,-2.24) 39(0.835,-0.405)
Top Overlay:
  circle w0.25: c-10.275,5.185 r0.125
  lines w0.2: -9.05,-12.075 -9.05,-12.8 -6.54,-12.8 ; -9.05,6.085 -9.05,12.8 ; 6.54,-12.8 9.05,-12.8 9.05,-12.075 ; 9.05,6.085 9.05,12.8 ; -9.05,12.8 9.05,12.8 ; -9.05,12.8 9.05,12.8
Keep-Out Layer:
  rectangle: -9,6.45 9,12.75
  rectangle: -9,6.45 9,12.75
Mechanical 5:
Mechanical 16:
  lines w0.1: -0.5,0 0.5,0 ; 0,-0.5 0,0.5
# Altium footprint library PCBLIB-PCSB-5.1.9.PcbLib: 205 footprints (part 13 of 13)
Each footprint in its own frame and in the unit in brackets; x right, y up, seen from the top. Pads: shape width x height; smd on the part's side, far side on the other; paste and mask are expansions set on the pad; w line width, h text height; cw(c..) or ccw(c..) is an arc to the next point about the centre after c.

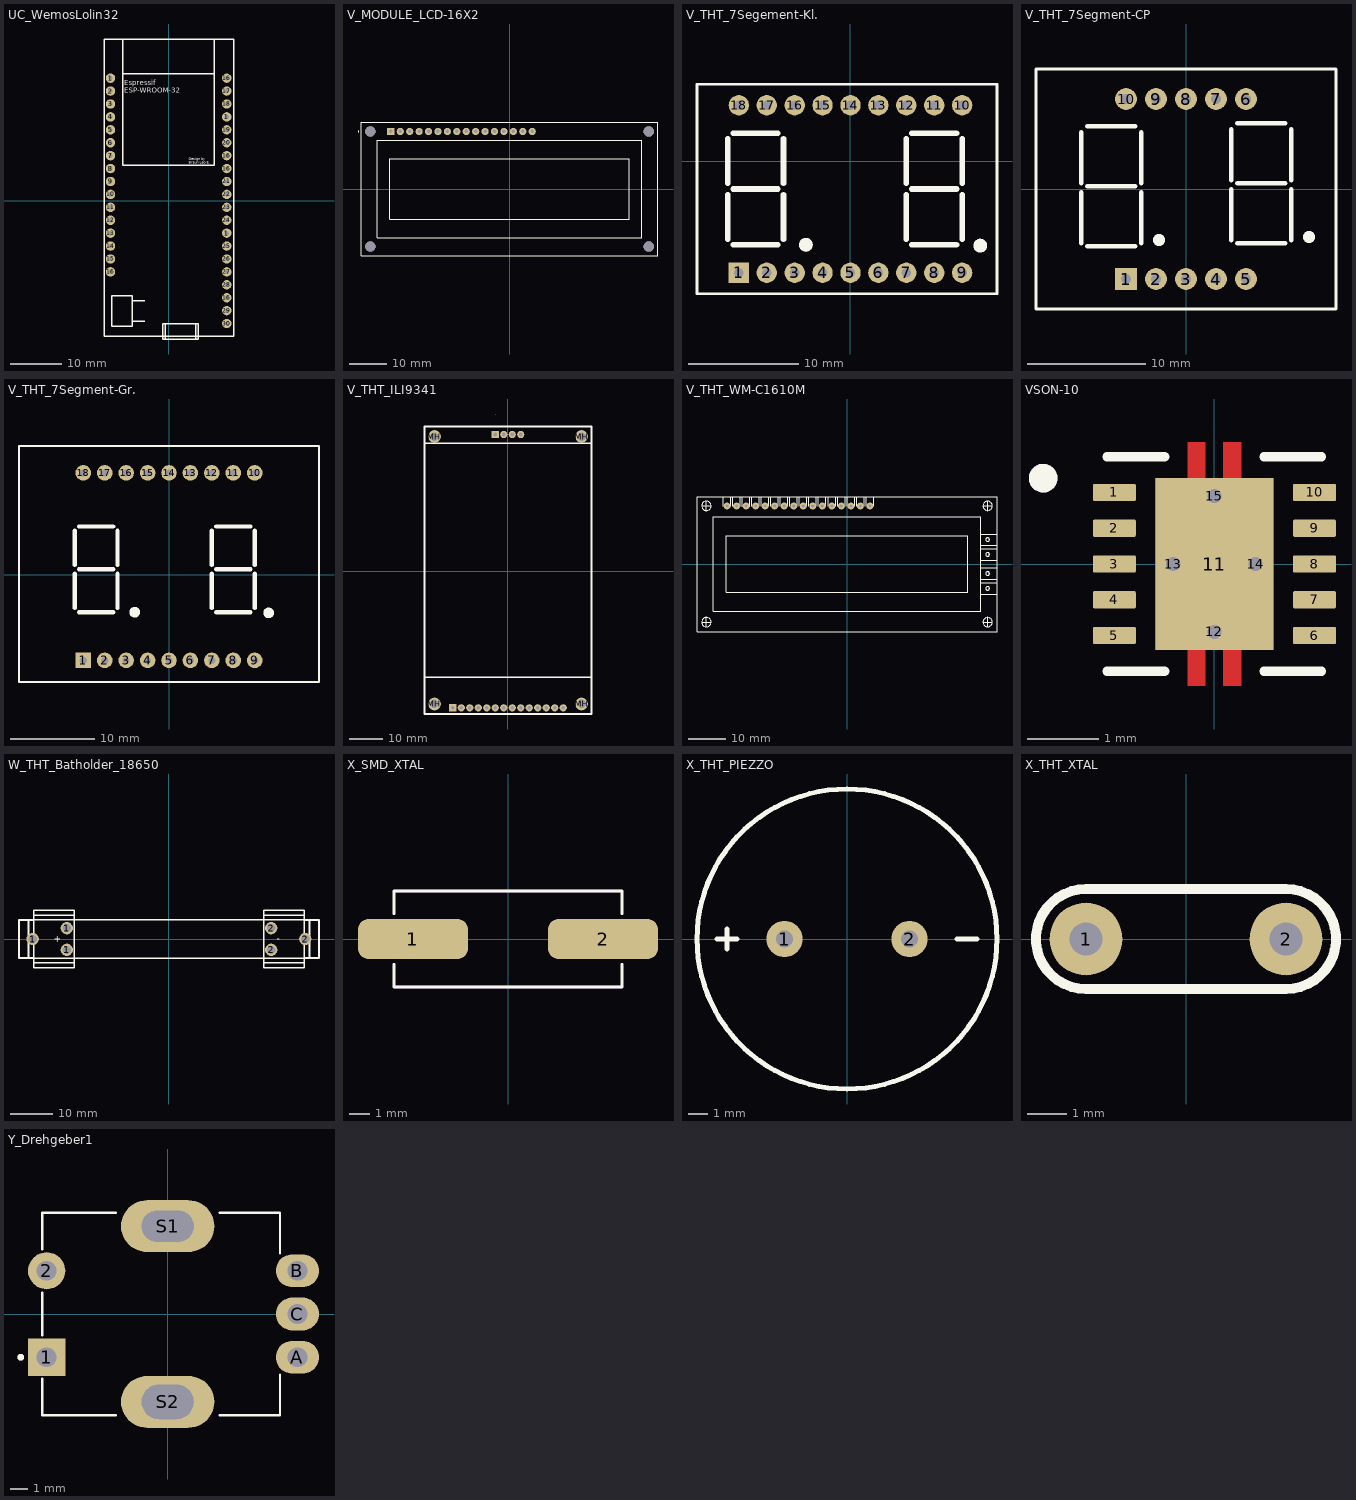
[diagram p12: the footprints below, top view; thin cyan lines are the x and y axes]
## UC_WemosLolin32 [mm] "LB-2024-04-20"
pads (36):
  round 1.85 hole 0.85: 1(-11.43,24.13) 1(11.43,-6.35) 1(11.43,16.51) 2(-11.43,21.59) 3(-11.43,19.05) 4(-11.43,16.51) 5(-11.43,13.97) 6(-11.43,11.43) 7(-11.43,8.89) 8(-11.43,6.35) 9(-11.43,3.81) 10(-11.43,1.27) 11(-11.43,-1.27) 12(-11.43,-3.81) 13(-11.43,-6.35) 14(-11.43,-8.89) 15(-11.43,-11.43) 16(-11.43,-13.97) 16(11.43,-19.05) 16(11.43,6.35) 16(11.43,8.89) 16(11.43,24.13) 17(11.43,21.59) 18(11.43,19.05) 19(11.43,13.97) 20(11.43,11.43) 21(11.43,3.81) 22(11.43,1.27) 23(11.43,-1.27) 24(11.43,-3.81) 25(11.43,-8.89) 26(11.43,-11.43) 27(11.43,-13.97) 28(11.43,-16.51) 29(11.43,-21.59) 30(11.43,-24.13)
Top Overlay:
  lines w0.254: -7.18,-23.67 -4.68,-23.67 ; -7.18,-19.67 -4.68,-19.67 ; -0.68,-24.17 -0.68,-27.17 -1.18,-27.17 ; 0.07,31.83 9,31.83 9,7 -9,7 -9,31.75 -9,25 9,25 ; 5.32,-27.17 5.32,-24.17 ; -1.18,-27.17 -1.18,-26.67 -1.18,-24.17 5.82,-24.17 5.82,-26.67 ; -1.18,-27.17 5.82,-27.17 5.82,-26.67 ; 5.82,-26.67 12.82,-26.67 ; 12.82,-26.67 -12.68,-26.67 -12.68,31.83 12.82,31.83 12.82,-26.67 ; -11.18,-24.67 -11.18,-18.67 -7.18,-18.67 -7.18,-24.67 -11.18,-24.67
  text "Design by / Braun Leo E." at 4,7.25 h0.5
  text "Espressif / ESP-WROOM-32" at -8.75,21.25 h1

## V_MODULE_LCD-16X2 [mm] "LB-2024-11-29"
height 14
pads (20):
  rect 1.95x1.95 hole 0.95: 1(-32,15.5)
  round 1.95 hole 0.95: 2(-29.46,15.5) 3(-26.92,15.5) 4(-24.38,15.5) 5(-21.84,15.5) 6(-19.3,15.5) 7(-16.76,15.5) 8(-14.22,15.5) 9(-11.68,15.5) 10(-9.14,15.5) 11(-6.6,15.5) 12(-4.06,15.5) 13(-1.52,15.5) 14(1.02,15.5) 15(3.56,15.5) 16(6.1,15.5)
  round 2.8 hole 2.8 unplated: ""(-37.5,-15.5) ""(-37.5,15.5) ""(37.5,-15.5) ""(37.5,15.5)
Top Overlay:
  circle w0.2: c-40.75,15.5 r0.1
  lines w0.127: -40,-18 40,-18 40,18 -40,18 -40,-18 ; -35.65,-13.15 35.65,-13.15 35.65,13.15 -35.65,13.15 -35.65,-13.15 ; -32.25,-8.2 32.25,-8.2 32.25,8.2 -32.25,8.2 -32.25,-8.2
Mechanical 13:
  circle w0.2: c-40.75,15.5 r0.1

## V_THT_7Segement-Kl. [mm] "LB-2024-04-19"
pads (18):
  rect 1.85x1.85 hole 0.85: 1(-10.16,-10.16)
  round 1.85 hole 0.85: 2(-7.62,-10.16) 3(-5.08,-10.16) 4(-2.54,-10.16) 5(0,-10.16) 6(2.54,-10.16) 7(5.08,-10.16) 8(7.62,-10.16) 9(10.16,-10.16) 10(10.16,5.08) 11(7.62,5.08) 12(5.08,5.08) 13(2.54,5.08) 14(0,5.08) 15(-2.54,5.08) 16(-5.08,5.08) 17(-7.62,5.08) 18(-10.16,5.08)
Top Overlay:
  circle w0.254: c11.811,-7.696 r0.508
  circle w0.254: c-4.064,-7.62 r0.508
  rectangle: 11.405,-8.103 12.217,-7.239
  rectangle: -4.47,-8.026 -3.607,-7.188
  lines w0.254: -13.97,-12.065 13.335,-12.065 13.335,6.985 -13.97,6.985 -13.97,-12.065
  lines w0.508: -11.176,-7.112 -11.176,-3.048 ; -11.176,-2.032 -11.176,2.032 ; -10.668,-7.62 -6.604,-7.62 ; -10.668,-2.54 -6.604,-2.54 ; -10.668,2.54 -6.604,2.54 ; -6.096,-7.112 -6.096,-3.048 ; -6.096,-2.032 -6.096,2.032 ; 5.08,-7.112 5.08,-3.048 ; 5.08,-2.032 5.08,2.032 ; 5.588,-7.62 9.652,-7.62 ; 5.588,-2.54 9.652,-2.54 ; 5.588,2.54 9.652,2.54 ; 10.16,-7.112 10.16,-3.048 ; 10.16,-2.032 10.16,2.032

## V_THT_7Segment-CP [mm] "LB-2024-04-19"
pads (10):
  rect 1.85x1.85 hole 0.85: 1(-5.08,-7.62)
  round 1.85 hole 0.85: 2(-2.54,-7.62) 3(0,-7.62) 4(2.54,-7.62) 5(5.08,-7.62) 6(5.08,7.62) 7(2.54,7.62) 8(0,7.62) 9(-2.54,7.62) 10(-5.08,7.62)
Top Overlay:
  circle w0.508: c10.414,-4.064 r0.254
  circle w0.508: c-2.286,-4.318 r0.254
  lines w0.254: 0,10.16 12.7,10.16 ; 12.7,10.16 12.7,-10.16 -12.7,-10.16 -12.7,10.16 12.7,10.16
  lines w0.381: -8.89,-4.572 -8.89,-0.254 ; -8.89,0.508 -8.89,4.826 ; -8.382,-4.826 -4.318,-4.826 ; -8.382,0.254 -4.318,0.254 ; -8.382,5.334 -4.318,5.334 ; -3.81,-4.572 -3.81,-0.254 ; -3.81,0.508 -3.81,4.826 ; 3.81,-4.318 3.81,0 ; 3.81,0.762 3.81,5.08 ; 4.318,-4.572 8.382,-4.572 ; 4.318,0.508 8.382,0.508 ; 4.318,5.588 8.382,5.588 ; 8.89,-4.318 8.89,0 ; 8.89,0.762 8.89,5.08

## V_THT_7Segment-Gr. [mm] "LB-2024-04-19"
pads (18):
  rect 1.85x1.85 hole 0.85: 1(-10.16,-10.16)
  round 1.85 hole 0.85: 2(-7.62,-10.16) 3(-5.08,-10.16) 4(-2.54,-10.16) 5(0,-10.16) 6(2.54,-10.16) 7(5.08,-10.16) 8(7.62,-10.16) 9(10.16,-10.16) 10(10.16,12.065) 11(7.62,12.065) 12(5.08,12.065) 13(2.54,12.065) 14(0,12.065) 15(-2.54,12.065) 16(-5.08,12.065) 17(-7.62,12.065) 18(-10.16,12.065)
Top Overlay:
  circle w0.254: c11.811,-4.521 r0.508
  circle w0.254: c-4.064,-4.445 r0.508
  rectangle: 11.405,-4.928 12.217,-4.064
  rectangle: -4.47,-4.851 -3.607,-4.013
  lines w0.254: -17.78,-12.7 17.78,-12.7 17.78,15.24 -17.78,15.24 -17.78,-12.7
  lines w0.508: -11.176,-3.937 -11.176,0.127 ; -11.176,1.143 -11.176,5.207 ; -10.668,-4.445 -6.604,-4.445 ; -10.668,0.635 -6.604,0.635 ; -10.668,5.715 -6.604,5.715 ; -6.096,-3.937 -6.096,0.127 ; -6.096,1.143 -6.096,5.207 ; 5.08,-3.937 5.08,0.127 ; 5.08,1.143 5.08,5.207 ; 5.588,-4.445 9.652,-4.445 ; 5.588,0.635 9.652,0.635 ; 5.588,5.715 9.652,5.715 ; 10.16,-3.937 10.16,0.127 ; 10.16,1.143 10.16,5.207

## V_THT_ILI9341 [mm] "LB-2024-04-19"
pads (22):
  rect 2.15x2.15 hole 1.15: A1(-3.81,40.88) B1(-16.51,-40.88)
  round 2.15 hole 1.15: A2(-1.27,40.88) A3(1.27,40.88) A4(3.81,40.88) B2(-13.97,-40.88) B3(-11.43,-40.88) B4(-8.89,-40.88) B5(-6.35,-40.88) B6(-3.81,-40.88) B7(-1.27,-40.88) B8(1.27,-40.88) B9(3.81,-40.88) B10(6.35,-40.88) B11(8.89,-40.88) B12(11.43,-40.88) B13(13.97,-40.88) B14(16.51,-40.88)
  round 3.81 hole 2.54: MH(-22,-39.73) MH(-22,40.27) MH(22,-39.73) MH(22,40.27)
Top Overlay:
  lines w0.1: -3.81,46.92 cw(c-3.81,46.97) -3.81,47.02 cw(c-3.81,46.97) -3.81,46.92
  lines w0.5: -25,-31.73 25,-31.73 ; -25,38.27 25,38.27 ; -25,-42.73 -25,43.27 25,43.27 25,1.27 25,-42.73 -25,-42.73

## V_THT_WM-C1610M [mm] "LB-2024-04-19"
pads (16):
  round 1.85 hole 0.85: 1(-32,15.5) 2(-29.46,15.5) 3(-26.92,15.5) 4(-24.38,15.5) 5(-21.84,15.5) 6(-19.3,15.5) 7(-16.76,15.5) 8(-14.22,15.5) 9(-11.68,15.5) 10(-9.14,15.5) 11(-6.6,15.5) 12(-4.06,15.5) 13(-1.52,15.5) 14(1.02,15.5) 15(3.56,15.5) 16(6.1,15.5)
Top Overlay:
  circle w0.2: c37.49,-15.462 r1.25
  circle w0.2: c37.49,-6.462 r0.5
  circle w0.2: c37.49,-2.502 r0.5
  circle w0.2: c37.49,2.578 r0.5
  circle w0.2: c37.49,6.538 r0.5
  circle w0.2: c37.49,15.538 r1.25
  circle w0.2: c-37.51,-15.462 r1.25
  circle w0.2: c-37.51,15.538 r1.25
  lines w0.1: -38.75,-15.462 -36.26,-15.462 ; -38.75,15.538 -36.26,15.538 ; -37.51,-16.75 -37.51,-14.25 ; -37.51,14.25 -37.51,16.75 ; 36.25,-15.462 38.74,-15.462 ; 36.25,15.538 38.74,15.538 ; 37.49,-16.75 37.49,-14.25 ; 37.49,14.25 37.49,16.75
  lines w0.2: -33.01,15.498 -33.01,18.038 ; -31.01,15.498 -31.01,18.038 ; -30.47,15.498 -30.47,18.038 ; -28.47,15.498 -28.47,18.038 ; -27.93,15.338 -27.93,18.038 ; -25.93,15.338 -25.93,18.038 ; -25.39,15.498 -25.39,18.038 ; -23.39,15.498 -23.39,18.038 ; -22.85,15.498 -22.85,18.038 ; -20.85,15.498 -20.85,18.038 ; -20.31,15.498 -20.31,18.038 ; -18.31,15.498 -18.31,18.038 ; -17.77,15.498 -17.77,18.038 ; -15.77,15.498 -15.77,18.038 ; -15.23,15.498 -15.23,18.038 ; -13.23,15.498 -13.23,18.038 ; -12.69,15.498 -12.69,18.038 ; -10.69,15.498 -10.69,18.038 ; -10.15,15.468 -10.15,18.038 ; -8.15,15.468 -8.15,18.038 ; -7.61,15.468 -7.61,18.038 ; -5.61,15.468 -5.61,18.038 ; -5.07,15.498 -5.07,18.038 ; -3.07,15.498 -3.07,18.038 ; -2.53,15.498 -2.53,18.038 ; -0.53,15.498 -0.53,18.038 ; 0.01,15.498 0.01,18.038 ; 2.01,15.498 2.01,18.038 ; 2.55,15.498 2.55,18.038 ; 4.55,15.498 4.55,18.038 ; 5.09,15.498 5.09,18.038 ; 7.09,15.498 7.09,18.038 ; 35.59,-7.962 39.99,-7.962 ; 35.59,-4.962 39.99,-4.962 ; 35.59,-4.002 39.99,-4.002 ; 35.59,-1.002 39.99,-1.002 ; 35.59,1.078 39.99,1.078 ; 35.59,4.078 39.99,4.078 ; 35.59,5.038 39.99,5.038 ; 35.59,8.038 39.99,8.038 ; -40.01,-17.962 -40.01,18.038 39.99,18.038 39.99,-17.962 -40.01,-17.962 ; -35.61,-12.562 35.59,-12.562 35.59,12.638 -35.61,12.638 -35.61,-12.562 ; -32.24,-7.462 -32.24,7.538 32.22,7.538 32.22,-7.462 -32.24,-7.462

## VSON-10 [mm] "LB-2024-09-01"
pads (15):
  rrect15% 0.6x0.24 smd paste-0.02 mask+0.05: 1(-1.4,1) 2(-1.4,0.5) 3(-1.4,0) 4(-1.4,-0.5) 5(-1.4,-1) 6(1.4,-1) 7(1.4,-0.5) 8(1.4,0) 9(1.4,0.5) 10(1.4,1)
  rect 1.65x2.4 smd paste-0.02 mask+0.05: 11(0,0)
  round 0.3 hole 0.2 mask+0: 12(0,-0.95) 13(-0.575,0) 14(0.575,0) 15(0,0.95)
Top Layer:
  region: 0.375,1.2 0.825,1.2 0.825,-1.2 0.375,-1.2 0.375,-1.7 0.125,-1.7 0.125,-1.2 -0.125,-1.2 -0.125,-1.7 -0.375,-1.7 -0.375,-1.2 -0.825,-1.2 -0.825,1.2 -0.375,1.2 -0.375,1.7 -0.125,1.7 -0.125,1.2 0.125,1.2 0.125,1.7 0.375,1.7
Top Overlay:
  circle w0.2: c-2.395,1.2 r0.1
  lines w0.127: -1.5,-1.5 -0.695,-1.5 ; -1.5,1.5 -0.695,1.5 ; 0.695,-1.5 1.5,-1.5 ; 0.695,1.5 1.5,1.5
Top Paste:
  region: 0.75,-1.16 -0.75,-1.16 -0.75,-0.1 0.75,-0.1
  region: 0.75,0.1 -0.75,0.1 -0.75,1.16 0.75,1.16
  region: -0.125,-1.7 -0.375,-1.7 -0.375,-1.36 -0.125,-1.36
  region: 0.375,-1.7 0.125,-1.7 0.125,-1.36 0.375,-1.36
  region: 0.375,1.36 0.125,1.36 0.125,1.7 0.375,1.7
  region: -0.125,1.36 -0.375,1.36 -0.375,1.7 -0.125,1.7
Mechanical 13:
  circle w0.2: c-2.395,1.2 r0.1

## W_THT_Batholder_18650 [mm] "LB-2024-04-25"
height 17
pads (6):
  round 2.9 hole 1.9: 1(-32,0) 1(-24,-2.54) 1(-24,2.54) 2(24.006,-2.54) 2(24.006,2.54) 2(32,0)
Top Overlay:
  lines w0.4: -31.74,-6.75 -22.27,-6.75 ; -31.74,-6.71 -31.74,-5.552 -29.08,-5.552 -22.272,-5.552 ; -31.74,-5.492 -31.74,5.552 ; -31.74,-4.45 -35.22,-4.45 -35.22,4.45 -31.74,4.45 ; -31.74,6.71 -31.74,5.552 ; -31.74,6.75 -22.27,6.75 ; -22.272,5.552 -29.08,5.552 -31.74,5.552 ; -22.22,-6.75 -22.22,-5.552 -22.22,5.552 -22.22,6.75 ; 22.226,-6.75 22.226,-5.552 22.226,5.552 22.226,6.75 ; 22.276,-6.75 31.746,-6.75 ; 22.276,6.75 31.746,6.75 ; 22.278,-5.552 29.086,-5.552 31.746,-5.552 ; 22.278,5.552 29.086,5.552 31.746,5.552 31.746,6.71 ; 31.746,-6.71 31.746,-5.552 ; 31.746,-4.45 35.226,-4.45 35.226,4.45 31.746,4.45 ; 31.746,5.492 31.746,-5.552 ; -33,-4.5 -33,0 -33,4.5 33,4.5 33,0 33,-4.5 -33,-4.5
  text "-" at 25.3,-0.7 h1.52
  text "+" at -25.3,0.7 h1.52

## X_SMD_XTAL [mm] "LB-2024-04-17"
pads (2):
  rrect50% 5.5x2 smd paste-0.02 mask+0.05: 1(-4.75,0) 2(4.75,0)
Top Overlay:
  lines w0.127: -5.7,-1.254 -5.7,-2.4 5.7,-2.4 5.7,-1.254 ; -5.7,1.254 -5.7,2.4 5.7,2.4 5.7,1.254
Mechanical 13:
  lines w0.127: -5.7,-2.4 5.7,-2.4 ; -5.7,2.4 5.7,2.4

## X_THT_PIEZZO [mm] "LB-2024-04-18"
pads (2):
  round 1.85 hole 0.85: 1(-3.175,0) 2(3.175,0)
Top Overlay:
  circle w0.254: c0,0 r7.62
  lines w0.254: -6.604,0 -5.588,0 ; -6.096,-0.508 -6.096,0.508 ; 5.588,0 6.604,0

## X_THT_XTAL [mm] "LB-2024-04-17"
pads (2):
  round 1.85 hole 0.85: 1(-2.54,0) 2(2.54,0)
Top Overlay:
  lines w0.254: -2.54,-1.27 cw(c-2.54,0) -2.54,1.27 2.54,1.27 cw(c2.54,0) 2.54,-1.27 -2.54,-1.27

## Y_Drehgeber1 [mm] "LB-2024-04-19"
pads (7):
  rect 2.15x2.15 hole 1.15: 1(-7,-2.5)
  round 2.15 hole 1.15: 2(-7,2.5)
  oval 2.5x1.9 hole 1.15: A(7.5,-2.5) B(7.5,2.5) C(7.5,0)
  oval 5.4x3 hole 1.8 slot 3 at 0 deg: S1(0,5.08)
  oval 5.4x3 hole 2 slot 3 at 0 deg: S2(0,-5.08)
Top Overlay:
  circle w0.2: c-8.5,-2.5 r0.1
  lines w0.127: -7.25,-3.75 -7.25,-5.85 -3,-5.85 ; -7.25,-1.25 -7.25,1.25 ; -7.25,3.75 -7.25,5.85 -3,5.85 ; 3,-5.85 6.5,-5.85 6.5,-3.5 ; 3,5.85 6.5,5.85 6.5,3.5
Mechanical 13:
  circle w0.2: c-8.5,-2.5 r0.1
